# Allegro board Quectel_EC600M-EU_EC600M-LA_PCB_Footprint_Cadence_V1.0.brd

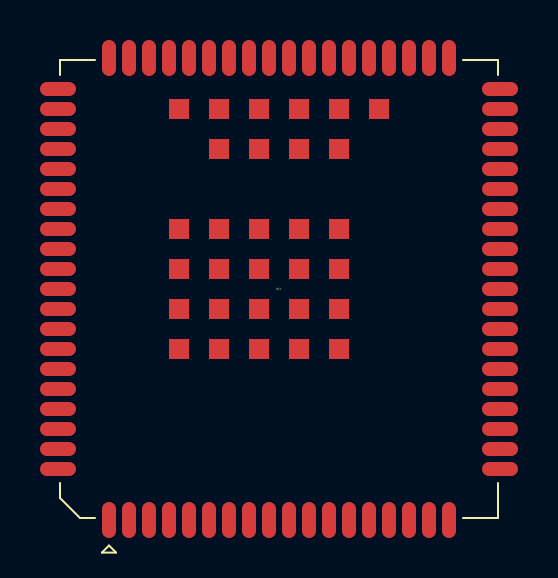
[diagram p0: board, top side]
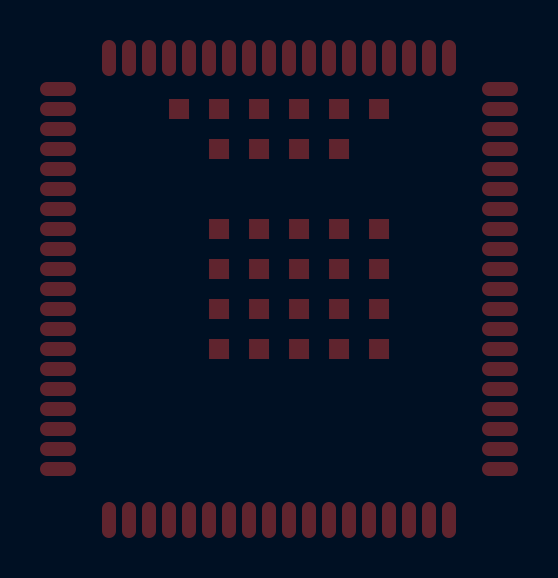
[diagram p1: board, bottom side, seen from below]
No outline. copper layers: TOP, BOTTOM. Coordinates in mm from the lowest, leftmost part position.

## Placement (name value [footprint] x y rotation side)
REF  -  [unnamed]  0 0 0 top

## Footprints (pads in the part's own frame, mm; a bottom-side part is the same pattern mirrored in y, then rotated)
unnamed
  oval 0.7x1.8 smd: 1(-8.5,-11.55) 2(-7.5,-11.55) 3(-6.5,-11.55) 4(-5.5,-11.55) 5(-4.5,-11.55) 6(-3.5,-11.55) 7(-2.5,-11.55) 8(-1.5,-11.55) 9(-0.5,-11.55) 10(0.5,-11.55) 11(1.5,-11.55) 12(2.5,-11.55) 13(3.5,-11.55) 14(4.5,-11.55) 15(5.5,-11.55) 16(6.5,-11.55) 17(7.5,-11.55) 18(8.5,-11.55) 39(8.5,11.55) 40(7.5,11.55) 41(6.5,11.55) 42(5.5,11.55) 43(4.5,11.55) 44(3.5,11.55) 45(2.5,11.55) 46(1.5,11.55) 47(0.5,11.55) 48(-0.5,11.55) 49(-1.5,11.55) 50(-2.5,11.55) 51(-3.5,11.55) 52(-4.5,11.55) 53(-5.5,11.55) 54(-6.5,11.55) 55(-7.5,11.55) 56(-8.5,11.55)
  oval 1.8x0.7 smd: 19(11.05,-9) 20(11.05,-8) 21(11.05,-7) 22(11.05,-6) 23(11.05,-5) 24(11.05,-4) 25(11.05,-3) 26(11.05,-2) 27(11.05,-1) 28(11.05,0) 29(11.05,1) 30(11.05,2) 31(11.05,3) 32(11.05,4) 33(11.05,5) 34(11.05,6) 35(11.05,7) 36(11.05,8) 37(11.05,9) 38(11.05,10) 57(-11.05,10) 58(-11.05,9) 59(-11.05,8) 60(-11.05,7) 61(-11.05,6) 62(-11.05,5) 63(-11.05,4) 64(-11.05,3) 65(-11.05,2) 66(-11.05,1) 67(-11.05,0) 68(-11.05,-1) 69(-11.05,-2) 70(-11.05,-3) 71(-11.05,-4) 72(-11.05,-5) 73(-11.05,-6) 74(-11.05,-7) 75(-11.05,-8) 76(-11.05,-9)
  rect 1x1 smd: 77(-3,-3) 78(-1,-3) 79(1,-3) 80(3,-3) 81(3,-1) 82(3,1) 83(3,3) 84(1,3) 85(-1,3) 86(-3,3) 87(-3,1) 88(-3,-1) 89(-1,-1) 90(1,-1) 91(1,1) 92(-1,1) 109(-5,3) 110(-5,1) 111(-5,-1) 112(-5,-3) 130(5,9) 131(3,9) 132(1,9) 133(-1,9) 134(-3,9) 135(-5,9) 145(3,7) 146(1,7) 147(-1,7) 148(-3,7)

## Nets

Pads without a net: REF 1 2 3 4 5 6 7 8 9 10 11 12 13 14 15 16 17 18 19 20 21 22 23 24 25 26 27 28 29 30 31 32 33 34 35 36 37 38 39 40 41 42 43 44 45 46 47 48 49 50 51 52 53 54 55 56 57 58 59 60 61 62 63 64 65 66 67 68 69 70 71 72 73 74 75 76 77 78 79 80 81 82 83 84 85 86 87 88 89 90 91 92 109 110 111 112 130 131 132 133 134 135 145 146 147 148
